One B-rep face of a CAD part: STEP entity #463.
In plain terms, the conical face has half-angle 70 degrees and reference radius 0.246 mm.
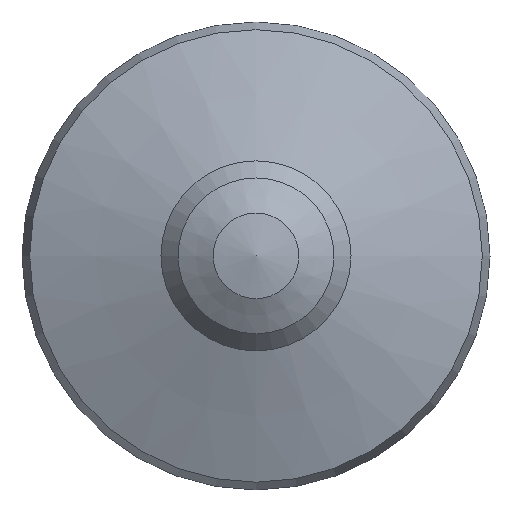
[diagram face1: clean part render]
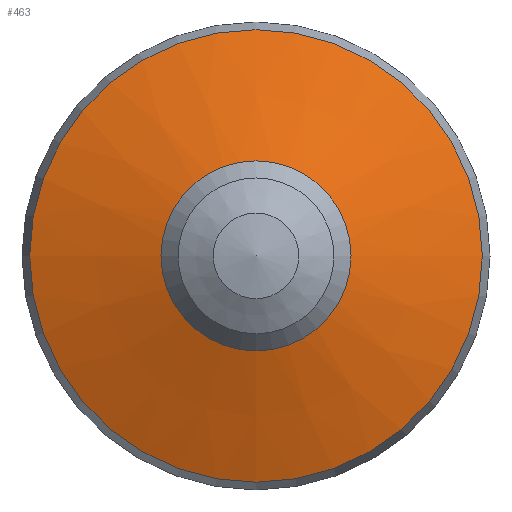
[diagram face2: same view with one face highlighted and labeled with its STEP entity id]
Its self-contained STEP definition (entity closure, numbers rounded to 3 decimals):
#463 = ADVANCED_FACE('',(#464),#477,.T.);
#464 = FACE_BOUND('',#465,.F.);
#465 = EDGE_LOOP('',(#466,#500,#523,#550));
#466 = ORIENTED_EDGE('',*,*,#467,.T.);
#467 = EDGE_CURVE('',#468,#468,#470,.T.);
#468 = VERTEX_POINT('',#469);
#469 = CARTESIAN_POINT('',(0.246,0.,0.33));
#470 = SURFACE_CURVE('',#471,(#476,#488),.PCURVE_S1.);
#471 = CIRCLE('',#472,0.246);
#472 = AXIS2_PLACEMENT_3D('',#473,#474,#475);
#473 = CARTESIAN_POINT('',(0.,0.,0.33));
#474 = DIRECTION('',(0.,0.,1.));
#475 = DIRECTION('',(1.,0.,-0.));
#476 = PCURVE('',#477,#482);
#477 = CONICAL_SURFACE('',#478,0.246,1.222);
#478 = AXIS2_PLACEMENT_3D('',#479,#480,#481);
#479 = CARTESIAN_POINT('',(0.,0.,0.33));
#480 = DIRECTION('',(-0.,-0.,-1.));
#481 = DIRECTION('',(1.,0.,0.));
#482 = DEFINITIONAL_REPRESENTATION('',(#483),#487);
#483 = LINE('',#484,#485);
#484 = CARTESIAN_POINT('',(-0.,0.));
#485 = VECTOR('',#486,1.);
#486 = DIRECTION('',(-1.,0.));
#487 = ( GEOMETRIC_REPRESENTATION_CONTEXT(2) 
PARAMETRIC_REPRESENTATION_CONTEXT() REPRESENTATION_CONTEXT('2D SPACE',''
  ) );
#488 = PCURVE('',#489,#494);
#489 = CYLINDRICAL_SURFACE('',#490,0.246);
#490 = AXIS2_PLACEMENT_3D('',#491,#492,#493);
#491 = CARTESIAN_POINT('',(0.,0.,0.305));
#492 = DIRECTION('',(0.,0.,1.));
#493 = DIRECTION('',(1.,0.,-0.));
#494 = DEFINITIONAL_REPRESENTATION('',(#495),#499);
#495 = LINE('',#496,#497);
#496 = CARTESIAN_POINT('',(0.,0.025));
#497 = VECTOR('',#498,1.);
#498 = DIRECTION('',(1.,0.));
#499 = ( GEOMETRIC_REPRESENTATION_CONTEXT(2) 
PARAMETRIC_REPRESENTATION_CONTEXT() REPRESENTATION_CONTEXT('2D SPACE',''
  ) );
#500 = ORIENTED_EDGE('',*,*,#501,.T.);
#501 = EDGE_CURVE('',#468,#502,#504,.T.);
#502 = VERTEX_POINT('',#503);
#503 = CARTESIAN_POINT('',(0.585,0.,0.207));
#504 = SEAM_CURVE('',#505,(#509,#516),.PCURVE_S1.);
#505 = LINE('',#506,#507);
#506 = CARTESIAN_POINT('',(0.246,0.,0.33));
#507 = VECTOR('',#508,1.);
#508 = DIRECTION('',(0.94,0.,-0.342));
#509 = PCURVE('',#477,#510);
#510 = DEFINITIONAL_REPRESENTATION('',(#511),#515);
#511 = LINE('',#512,#513);
#512 = CARTESIAN_POINT('',(-0.,0.));
#513 = VECTOR('',#514,1.);
#514 = DIRECTION('',(-0.,1.));
#515 = ( GEOMETRIC_REPRESENTATION_CONTEXT(2) 
PARAMETRIC_REPRESENTATION_CONTEXT() REPRESENTATION_CONTEXT('2D SPACE',''
  ) );
#516 = PCURVE('',#477,#517);
#517 = DEFINITIONAL_REPRESENTATION('',(#518),#522);
#518 = LINE('',#519,#520);
#519 = CARTESIAN_POINT('',(-6.283,0.));
#520 = VECTOR('',#521,1.);
#521 = DIRECTION('',(-0.,1.));
#522 = ( GEOMETRIC_REPRESENTATION_CONTEXT(2) 
PARAMETRIC_REPRESENTATION_CONTEXT() REPRESENTATION_CONTEXT('2D SPACE',''
  ) );
#523 = ORIENTED_EDGE('',*,*,#524,.F.);
#524 = EDGE_CURVE('',#502,#502,#525,.T.);
#525 = SURFACE_CURVE('',#526,(#531,#538),.PCURVE_S1.);
#526 = CIRCLE('',#527,0.585);
#527 = AXIS2_PLACEMENT_3D('',#528,#529,#530);
#528 = CARTESIAN_POINT('',(0.,0.,0.207));
#529 = DIRECTION('',(0.,0.,1.));
#530 = DIRECTION('',(1.,0.,-0.));
#531 = PCURVE('',#477,#532);
#532 = DEFINITIONAL_REPRESENTATION('',(#533),#537);
#533 = LINE('',#534,#535);
#534 = CARTESIAN_POINT('',(-0.,0.123));
#535 = VECTOR('',#536,1.);
#536 = DIRECTION('',(-1.,0.));
#537 = ( GEOMETRIC_REPRESENTATION_CONTEXT(2) 
PARAMETRIC_REPRESENTATION_CONTEXT() REPRESENTATION_CONTEXT('2D SPACE',''
  ) );
#538 = PCURVE('',#539,#544);
#539 = CONICAL_SURFACE('',#540,0.585,0.381);
#540 = AXIS2_PLACEMENT_3D('',#541,#542,#543);
#541 = CARTESIAN_POINT('',(0.,0.,0.207));
#542 = DIRECTION('',(-0.,-0.,-1.));
#543 = DIRECTION('',(1.,0.,0.));
#544 = DEFINITIONAL_REPRESENTATION('',(#545),#549);
#545 = LINE('',#546,#547);
#546 = CARTESIAN_POINT('',(-0.,0.));
#547 = VECTOR('',#548,1.);
#548 = DIRECTION('',(-1.,0.));
#549 = ( GEOMETRIC_REPRESENTATION_CONTEXT(2) 
PARAMETRIC_REPRESENTATION_CONTEXT() REPRESENTATION_CONTEXT('2D SPACE',''
  ) );
#550 = ORIENTED_EDGE('',*,*,#501,.F.);
